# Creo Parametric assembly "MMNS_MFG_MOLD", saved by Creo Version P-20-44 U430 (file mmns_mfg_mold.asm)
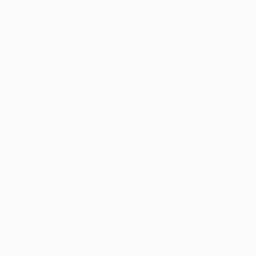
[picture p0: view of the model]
Units: millimeter Newton Second (mmNs); MM, TONNE, SECS

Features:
  1. datum plane "MOLD_RIGHT"
  2. datum plane "MAIN_PARTING_PLN"
  3. datum plane "MOLD_FRONT"
  4. coordinate system

Other named items: MOLD_DEF_CSYS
